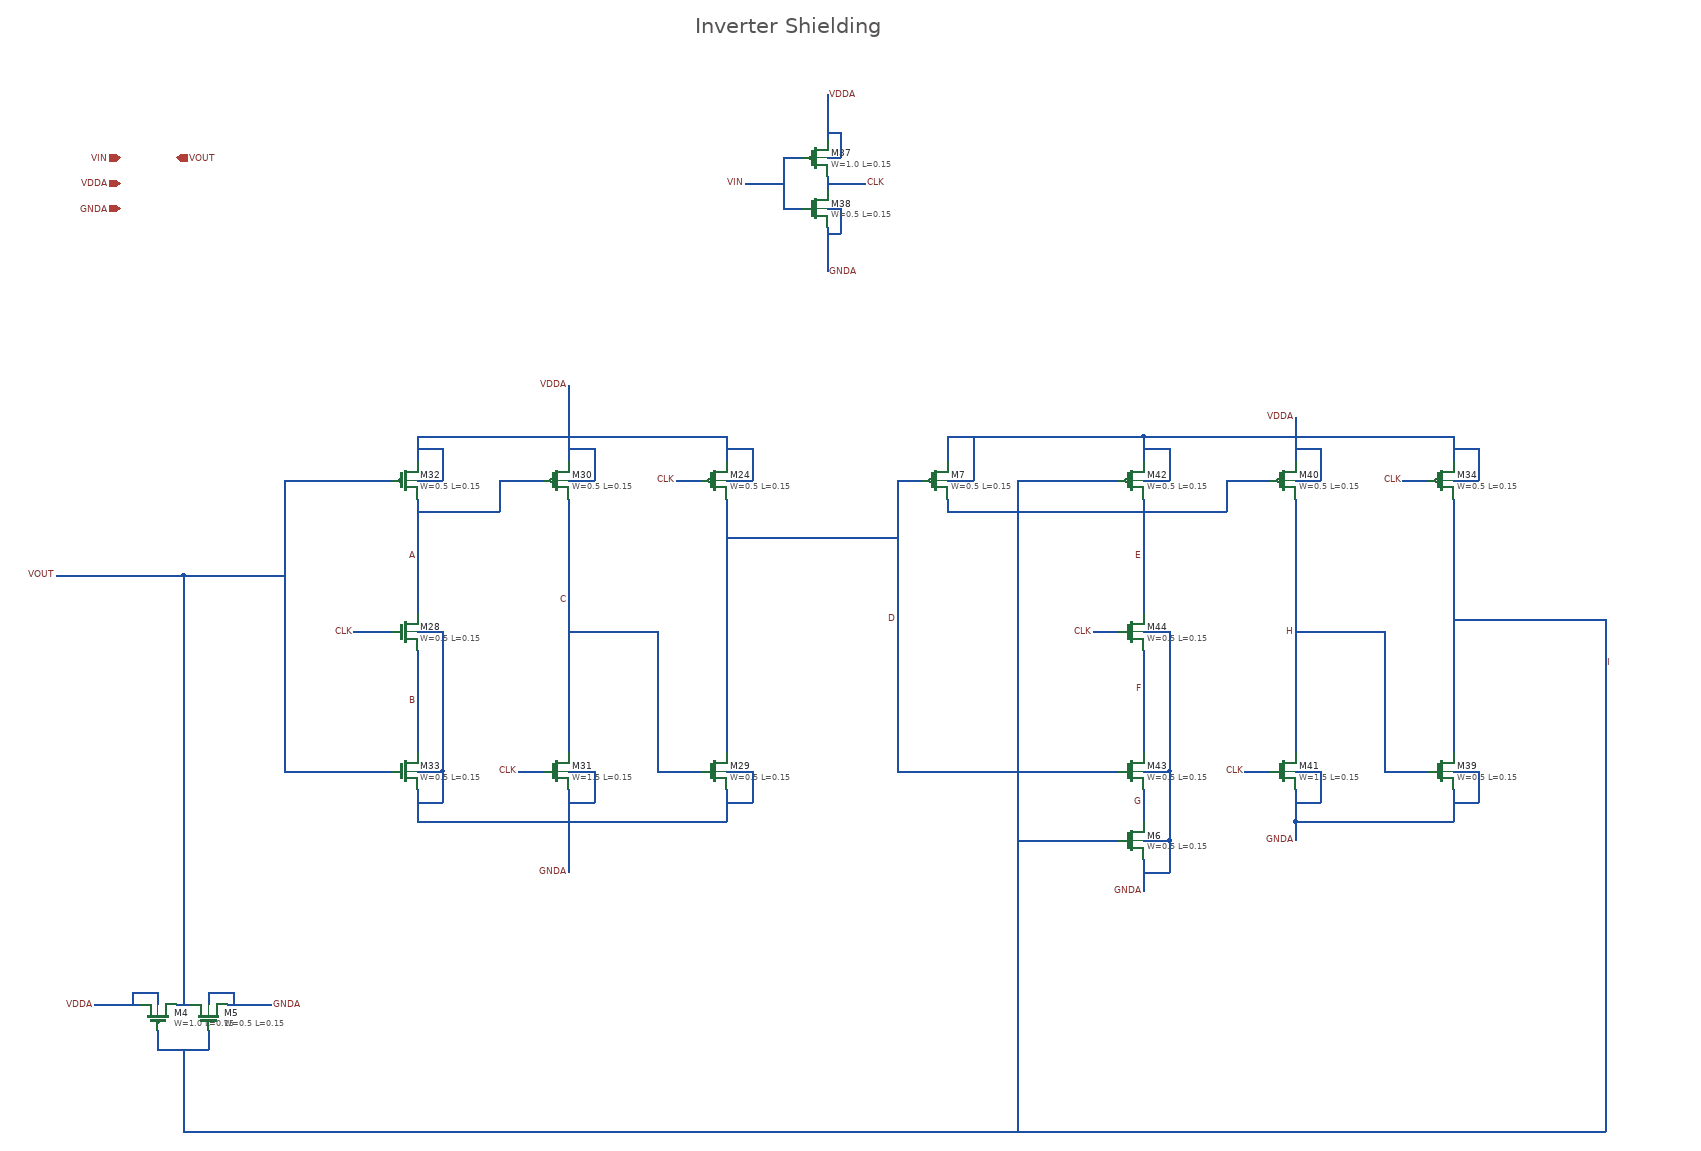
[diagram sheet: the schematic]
v {xschem version=3.4.6 file_version=1.2}
G {}
K {}
V {}
S {}
E {}
T {Inverter Shielding} 2280 -2010 0 0 1 1 {}
N 2330 -1350 2330 -1310 {
lab=VDDA}
N 2330 -1280 2370 -1280 {
lab=VDDA}
N 2370 -1330 2370 -1280 {
lab=VDDA}
N 2330 -1330 2370 -1330 {
lab=VDDA}
N 2330 -770 2370 -770 {
lab=GNDA}
N 2330 -790 2330 -740 {
lab=GNDA}
N 2330 -820 2370 -820 {
lab=GNDA}
N 2080 -1350 2080 -1310 {
lab=VDDA}
N 2080 -1280 2120 -1280 {
lab=VDDA}
N 2120 -1330 2120 -1280 {
lab=VDDA}
N 2080 -1330 2120 -1330 {
lab=VDDA}
N 2080 -770 2120 -770 {
lab=GNDA}
N 2080 -790 2080 -740 {
lab=GNDA}
N 2080 -820 2120 -820 {
lab=GNDA}
N 1840 -1350 1840 -1310 {
lab=VDDA}
N 1840 -1280 1880 -1280 {
lab=VDDA}
N 1880 -1330 1880 -1280 {
lab=VDDA}
N 1840 -1330 1880 -1330 {
lab=VDDA}
N 1840 -770 1880 -770 {
lab=GNDA}
N 1840 -790 1840 -740 {
lab=GNDA}
N 1840 -820 1880 -820 {
lab=GNDA}
N 2080 -1040 2220 -1040 {
lab=C}
N 1630 -1280 1800 -1280 {
lab=VOUT}
N 1630 -1280 1630 -910 {
lab=VOUT}
N 1740 -1040 1800 -1040 {
lab=CLK}
N 1880 -820 1880 -770 {
lab=GNDA}
N 2370 -820 2370 -770 {
lab=GNDA}
N 1840 -1350 2330 -1350 {
lab=VDDA}
N 2080 -1430 2080 -1350 {
lab=VDDA}
N 1840 -740 2330 -740 {
lab=GNDA}
N 2080 -740 2080 -660 {
lab=GNDA}
N 1630 -820 1800 -820 {
lab=VOUT}
N 1630 -910 1630 -820 {
lab=VOUT}
N 2000 -820 2040 -820 {
lab=CLK}
N 2120 -820 2120 -770 {
lab=GNDA}
N 2220 -820 2290 -820 {
lab=C}
N 1840 -1040 1880 -1040 {
lab=GNDA}
N 1880 -1040 1880 -820 {
lab=GNDA}
N 1840 -1230 1970 -1230 {
lab=A}
N 1970 -1280 1970 -1230 {
lab=A}
N 1970 -1280 2040 -1280 {
lab=A}
N 2250 -1280 2290 -1280 {
lab=CLK}
N 3480 -1350 3480 -1310 {
lab=VDDA}
N 3480 -1280 3520 -1280 {
lab=VDDA}
N 3520 -1330 3520 -1280 {
lab=VDDA}
N 3480 -1330 3520 -1330 {
lab=VDDA}
N 3480 -770 3520 -770 {
lab=GNDA}
N 3480 -790 3480 -740 {
lab=GNDA}
N 3480 -820 3520 -820 {
lab=GNDA}
N 3230 -1350 3230 -1310 {
lab=VDDA}
N 3230 -1280 3270 -1280 {
lab=VDDA}
N 3270 -1330 3270 -1280 {
lab=VDDA}
N 3230 -1330 3270 -1330 {
lab=VDDA}
N 3230 -770 3270 -770 {
lab=GNDA}
N 3230 -790 3230 -740 {
lab=GNDA}
N 3230 -820 3270 -820 {
lab=GNDA}
N 2990 -1350 2990 -1310 {
lab=VDDA}
N 2990 -1280 3030 -1280 {
lab=VDDA}
N 3030 -1330 3030 -1280 {
lab=VDDA}
N 2990 -1330 3030 -1330 {
lab=VDDA}
N 2990 -790 2990 -740 {
lab=G}
N 2990 -820 3030 -820 {
lab=GNDA}
N 3230 -1040 3370 -1040 {
lab=H}
N 2910 -1040 2950 -1040 {
lab=CLK}
N 3030 -820 3030 -770 {
lab=GNDA}
N 3520 -820 3520 -770 {
lab=GNDA}
N 2990 -1350 3480 -1350 {
lab=VDDA}
N 3230 -1380 3230 -1350 {
lab=VDDA}
N 3230 -740 3230 -710 {
lab=GNDA}
N 3150 -820 3190 -820 {
lab=CLK}
N 3270 -820 3270 -770 {
lab=GNDA}
N 3370 -820 3440 -820 {
lab=H}
N 2990 -1040 3030 -1040 {
lab=GNDA}
N 3030 -1040 3030 -820 {
lab=GNDA}
N 2990 -1230 3120 -1230 {
lab=E}
N 3120 -1280 3120 -1230 {
lab=E}
N 3120 -1280 3190 -1280 {
lab=E}
N 3400 -1280 3440 -1280 {
lab=CLK}
N 1460 -450 1480 -450 {
lab=VOUT}
N 1430 -410 1430 -380 {
lab=H}
N 1430 -380 1510 -380 {
lab=H}
N 1510 -410 1510 -380 {
lab=H}
N 1510 -470 1510 -450 {
lab=GNDA}
N 1510 -470 1550 -470 {
lab=GNDA}
N 1550 -470 1550 -450 {
lab=GNDA}
N 1330 -450 1400 -450 {
lab=VDDA}
N 1390 -470 1390 -450 {
lab=VDDA}
N 1390 -470 1430 -470 {
lab=VDDA}
N 1430 -470 1430 -450 {
lab=VDDA}
N 3480 -1060 3720 -1060 {
lab=H}
N 3720 -1060 3720 -250 {
lab=H}
N 1470 -250 3720 -250 {
lab=H}
N 3230 -740 3480 -740 {
lab=GNDA}
N 2990 -680 2990 -630 {
lab=GNDA}
N 3030 -770 3030 -710 {
lab=GNDA}
N 2990 -710 3030 -710 {
lab=GNDA}
N 3030 -710 3030 -660 {
lab=GNDA}
N 2990 -660 3030 -660 {
lab=GNDA}
N 2680 -1350 2680 -1310 {
lab=VDDA}
N 2680 -1350 2990 -1350 {
lab=VDDA}
N 2680 -1280 2720 -1280 {
lab=VDDA}
N 2720 -1350 2720 -1280 {
lab=VDDA}
N 2680 -1250 2680 -1230 {
lab=E}
N 2680 -1230 2990 -1230 {
lab=E}
N 2790 -1280 2950 -1280 {
lab=H}
N 2790 -710 2950 -710 {
lab=H}
N 2600 -1280 2600 -820 {
lab=D}
N 2600 -1280 2640 -1280 {
lab=D}
N 1470 -1130 1630 -1130 {
lab=VOUT}
N 1470 -380 1470 -250 {
lab=H}
N 1470 -1130 1470 -450 {
lab=VOUT}
N 2330 -1190 2600 -1190 {
lab=D}
N 2600 -820 2950 -820 {
lab=D}
N 2790 -1280 2790 -250 {
lab=H}
N 1840 -1250 1840 -1070 {
lab=A}
N 1840 -1010 1840 -850 {
lab=B}
N 2080 -1250 2080 -850 {
lab=C}
N 2220 -1040 2220 -820 {
lab=C}
N 2330 -1250 2330 -850 {
lab=D}
N 2990 -1010 2990 -850 {
lab=F}
N 2990 -1250 2990 -1070 {
lab=E}
N 3230 -1250 3230 -850 {
lab=H}
N 3370 -1040 3370 -820 {
lab=H}
N 3480 -1250 3480 -850 {
lab=H}
N 1540 -450 1610 -450 {
lab=GNDA}
N 1270 -1130 1470 -1130 {
lab=VOUT}
N 2490 -1760 2490 -1740 {
lab=CLK}
N 2420 -1790 2450 -1790 {
lab=VIN}
N 2420 -1790 2420 -1710 {
lab=VIN}
N 2420 -1710 2450 -1710 {
lab=VIN}
N 2490 -1710 2510 -1710 {
lab=GNDA}
N 2510 -1710 2510 -1670 {
lab=GNDA}
N 2490 -1670 2510 -1670 {
lab=GNDA}
N 2490 -1890 2490 -1820 {
lab=VDDA}
N 2490 -1830 2510 -1830 {
lab=VDDA}
N 2510 -1830 2510 -1790 {
lab=VDDA}
N 2490 -1790 2510 -1790 {
lab=VDDA}
N 2490 -1680 2490 -1610 {
lab=GNDA}
N 2360 -1750 2420 -1750 {
lab=VIN}
N 2490 -1750 2550 -1750 {
lab=CLK}
C {sky130_fd_pr/pfet_01v8.sym} 2310 -1280 0 0 {name=M24
L=0.15
W=0.5
nf=1
mult=1
ad="'int((nf+1)/2) * W/nf * 0.29'" 
pd="'2*int((nf+1)/2) * (W/nf + 0.29)'"
as="'int((nf+2)/2) * W/nf * 0.29'" 
ps="'2*int((nf+2)/2) * (W/nf + 0.29)'"
nrd="'0.29 / W'" nrs="'0.29 / W'"
sa=0 sb=0 sd=0
model=pfet_01v8
spiceprefix=X
}
C {sky130_fd_pr/nfet_01v8.sym} 2310 -820 0 0 {name=M29
L=0.15
W=0.5
nf=1 
mult=1
ad="'int((nf+1)/2) * W/nf * 0.29'" 
pd="'2*int((nf+1)/2) * (W/nf + 0.29)'"
as="'int((nf+2)/2) * W/nf * 0.29'" 
ps="'2*int((nf+2)/2) * (W/nf + 0.29)'"
nrd="'0.29 / W'" nrs="'0.29 / W'"
sa=0 sb=0 sd=0
model=nfet_01v8
spiceprefix=X
}
C {sky130_fd_pr/pfet_01v8.sym} 2060 -1280 0 0 {name=M30
L=0.15
W=0.5
nf=1
mult=1
ad="'int((nf+1)/2) * W/nf * 0.29'" 
pd="'2*int((nf+1)/2) * (W/nf + 0.29)'"
as="'int((nf+2)/2) * W/nf * 0.29'" 
ps="'2*int((nf+2)/2) * (W/nf + 0.29)'"
nrd="'0.29 / W'" nrs="'0.29 / W'"
sa=0 sb=0 sd=0
model=pfet_01v8
spiceprefix=X
}
C {sky130_fd_pr/nfet_01v8.sym} 2060 -820 0 0 {name=M31
L=0.15
W=1.5
nf=1 
mult=1
ad="'int((nf+1)/2) * W/nf * 0.29'" 
pd="'2*int((nf+1)/2) * (W/nf + 0.29)'"
as="'int((nf+2)/2) * W/nf * 0.29'" 
ps="'2*int((nf+2)/2) * (W/nf + 0.29)'"
nrd="'0.29 / W'" nrs="'0.29 / W'"
sa=0 sb=0 sd=0
model=nfet_01v8
spiceprefix=X
}
C {sky130_fd_pr/pfet_01v8.sym} 1820 -1280 0 0 {name=M32
L=0.15
W=0.5
nf=1
mult=1
ad="'int((nf+1)/2) * W/nf * 0.29'" 
pd="'2*int((nf+1)/2) * (W/nf + 0.29)'"
as="'int((nf+2)/2) * W/nf * 0.29'" 
ps="'2*int((nf+2)/2) * (W/nf + 0.29)'"
nrd="'0.29 / W'" nrs="'0.29 / W'"
sa=0 sb=0 sd=0
model=pfet_01v8
spiceprefix=X
}
C {sky130_fd_pr/nfet_01v8.sym} 1820 -820 0 0 {name=M33
L=0.15
W=0.5
nf=1 
mult=1
ad="'int((nf+1)/2) * W/nf * 0.29'" 
pd="'2*int((nf+1)/2) * (W/nf + 0.29)'"
as="'int((nf+2)/2) * W/nf * 0.29'" 
ps="'2*int((nf+2)/2) * (W/nf + 0.29)'"
nrd="'0.29 / W'" nrs="'0.29 / W'"
sa=0 sb=0 sd=0
model=nfet_01v8
spiceprefix=X
}
C {devices/lab_pin.sym} 1740 -1040 0 0 {name=p31 sig_type=std_logic lab=CLK}
C {devices/lab_pin.sym} 2000 -820 0 0 {name=p36 sig_type=std_logic lab=CLK}
C {sky130_fd_pr/nfet_01v8.sym} 1820 -1040 0 0 {name=M28
L=0.15
W=0.5
nf=1 
mult=1
ad="'int((nf+1)/2) * W/nf * 0.29'" 
pd="'2*int((nf+1)/2) * (W/nf + 0.29)'"
as="'int((nf+2)/2) * W/nf * 0.29'" 
ps="'2*int((nf+2)/2) * (W/nf + 0.29)'"
nrd="'0.29 / W'" nrs="'0.29 / W'"
sa=0 sb=0 sd=0
model=nfet_01v8
spiceprefix=X
}
C {devices/lab_pin.sym} 2250 -1280 0 0 {name=p32 sig_type=std_logic lab=CLK}
C {sky130_fd_pr/pfet_01v8.sym} 3460 -1280 0 0 {name=M34
L=0.15
W=0.5
nf=1
mult=1
ad="'int((nf+1)/2) * W/nf * 0.29'" 
pd="'2*int((nf+1)/2) * (W/nf + 0.29)'"
as="'int((nf+2)/2) * W/nf * 0.29'" 
ps="'2*int((nf+2)/2) * (W/nf + 0.29)'"
nrd="'0.29 / W'" nrs="'0.29 / W'"
sa=0 sb=0 sd=0
model=pfet_01v8
spiceprefix=X
}
C {sky130_fd_pr/nfet_01v8.sym} 3460 -820 0 0 {name=M39
L=0.15
W=0.5
nf=1 
mult=1
ad="'int((nf+1)/2) * W/nf * 0.29'" 
pd="'2*int((nf+1)/2) * (W/nf + 0.29)'"
as="'int((nf+2)/2) * W/nf * 0.29'" 
ps="'2*int((nf+2)/2) * (W/nf + 0.29)'"
nrd="'0.29 / W'" nrs="'0.29 / W'"
sa=0 sb=0 sd=0
model=nfet_01v8
spiceprefix=X
}
C {sky130_fd_pr/pfet_01v8.sym} 3210 -1280 0 0 {name=M40
L=0.15
W=0.5
nf=1
mult=1
ad="'int((nf+1)/2) * W/nf * 0.29'" 
pd="'2*int((nf+1)/2) * (W/nf + 0.29)'"
as="'int((nf+2)/2) * W/nf * 0.29'" 
ps="'2*int((nf+2)/2) * (W/nf + 0.29)'"
nrd="'0.29 / W'" nrs="'0.29 / W'"
sa=0 sb=0 sd=0
model=pfet_01v8
spiceprefix=X
}
C {sky130_fd_pr/nfet_01v8.sym} 3210 -820 0 0 {name=M41
L=0.15
W=1.5
nf=1 
mult=1
ad="'int((nf+1)/2) * W/nf * 0.29'" 
pd="'2*int((nf+1)/2) * (W/nf + 0.29)'"
as="'int((nf+2)/2) * W/nf * 0.29'" 
ps="'2*int((nf+2)/2) * (W/nf + 0.29)'"
nrd="'0.29 / W'" nrs="'0.29 / W'"
sa=0 sb=0 sd=0
model=nfet_01v8
spiceprefix=X
}
C {sky130_fd_pr/pfet_01v8.sym} 2970 -1280 0 0 {name=M42
L=0.15
W=0.5
nf=1
mult=1
ad="'int((nf+1)/2) * W/nf * 0.29'" 
pd="'2*int((nf+1)/2) * (W/nf + 0.29)'"
as="'int((nf+2)/2) * W/nf * 0.29'" 
ps="'2*int((nf+2)/2) * (W/nf + 0.29)'"
nrd="'0.29 / W'" nrs="'0.29 / W'"
sa=0 sb=0 sd=0
model=pfet_01v8
spiceprefix=X
}
C {sky130_fd_pr/nfet_01v8.sym} 2970 -820 0 0 {name=M43
L=0.15
W=0.5
nf=1 
mult=1
ad="'int((nf+1)/2) * W/nf * 0.29'" 
pd="'2*int((nf+1)/2) * (W/nf + 0.29)'"
as="'int((nf+2)/2) * W/nf * 0.29'" 
ps="'2*int((nf+2)/2) * (W/nf + 0.29)'"
nrd="'0.29 / W'" nrs="'0.29 / W'"
sa=0 sb=0 sd=0
model=nfet_01v8
spiceprefix=X
}
C {devices/lab_pin.sym} 2910 -1040 0 0 {name=p40 sig_type=std_logic lab=CLK}
C {devices/lab_pin.sym} 3150 -820 0 0 {name=p41 sig_type=std_logic lab=CLK}
C {sky130_fd_pr/nfet_01v8.sym} 2970 -1040 0 0 {name=M44
L=0.15
W=0.5
nf=1 
mult=1
ad="'int((nf+1)/2) * W/nf * 0.29'" 
pd="'2*int((nf+1)/2) * (W/nf + 0.29)'"
as="'int((nf+2)/2) * W/nf * 0.29'" 
ps="'2*int((nf+2)/2) * (W/nf + 0.29)'"
nrd="'0.29 / W'" nrs="'0.29 / W'"
sa=0 sb=0 sd=0
model=nfet_01v8
spiceprefix=X
}
C {devices/lab_pin.sym} 3400 -1280 0 0 {name=p44 sig_type=std_logic lab=CLK}
C {sky130_fd_pr/pfet_01v8.sym} 1430 -430 3 0 {name=M4
L=0.15
W=1.0
nf=2
mult=1
ad="'int((nf+1)/2) * W/nf * 0.29'" 
pd="'2*int((nf+1)/2) * (W/nf + 0.29)'"
as="'int((nf+2)/2) * W/nf * 0.29'" 
ps="'2*int((nf+2)/2) * (W/nf + 0.29)'"
nrd="'0.29 / W'" nrs="'0.29 / W'"
sa=0 sb=0 sd=0
model=pfet_01v8
spiceprefix=X
}
C {sky130_fd_pr/nfet_01v8.sym} 1510 -430 3 0 {name=M5
L=0.15
W=0.5
nf=1 
mult=1
ad="'int((nf+1)/2) * W/nf * 0.29'" 
pd="'2*int((nf+1)/2) * (W/nf + 0.29)'"
as="'int((nf+2)/2) * W/nf * 0.29'" 
ps="'2*int((nf+2)/2) * (W/nf + 0.29)'"
nrd="'0.29 / W'" nrs="'0.29 / W'"
sa=0 sb=0 sd=0
model=nfet_01v8
spiceprefix=X
}
C {sky130_fd_pr/nfet_01v8.sym} 2970 -710 0 0 {name=M6
L=0.15
W=0.5
nf=1 
mult=1
ad="'int((nf+1)/2) * W/nf * 0.29'" 
pd="'2*int((nf+1)/2) * (W/nf + 0.29)'"
as="'int((nf+2)/2) * W/nf * 0.29'" 
ps="'2*int((nf+2)/2) * (W/nf + 0.29)'"
nrd="'0.29 / W'" nrs="'0.29 / W'"
sa=0 sb=0 sd=0
model=nfet_01v8
spiceprefix=X
}
C {sky130_fd_pr/pfet_01v8.sym} 2660 -1280 0 0 {name=M7
L=0.15
W=0.5
nf=1
mult=1
ad="'int((nf+1)/2) * W/nf * 0.29'" 
pd="'2*int((nf+1)/2) * (W/nf + 0.29)'"
as="'int((nf+2)/2) * W/nf * 0.29'" 
ps="'2*int((nf+2)/2) * (W/nf + 0.29)'"
nrd="'0.29 / W'" nrs="'0.29 / W'"
sa=0 sb=0 sd=0
model=pfet_01v8
spiceprefix=X
}
C {devices/lab_pin.sym} 1610 -450 0 1 {name=p2 sig_type=std_logic lab=GNDA}
C {devices/lab_pin.sym} 1330 -450 0 0 {name=p1 sig_type=std_logic lab=VDDA}
C {devices/lab_pin.sym} 2080 -660 0 0 {name=p3 sig_type=std_logic lab=GNDA}
C {devices/lab_pin.sym} 2080 -1430 0 0 {name=p4 sig_type=std_logic lab=VDDA}
C {devices/lab_pin.sym} 3230 -1380 0 0 {name=p5 sig_type=std_logic lab=VDDA}
C {devices/lab_pin.sym} 3230 -710 0 0 {name=p6 sig_type=std_logic lab=GNDA}
C {devices/lab_pin.sym} 2990 -630 0 0 {name=p7 sig_type=std_logic lab=GNDA}
C {devices/lab_pin.sym} 1270 -1130 0 0 {name=p8 sig_type=std_logic lab=VOUT}
C {devices/ipin.sym} 1370 -1790 0 0 {name=p9 lab=VIN}
C {devices/opin.sym} 1460 -1790 0 0 {name=p10 lab=VOUT}
C {devices/ipin.sym} 1370 -1750 0 0 {name=p11 lab=VDDA}
C {devices/ipin.sym} 1370 -1710 0 0 {name=p12 lab=GNDA}
C {sky130_fd_pr/pfet_01v8.sym} 2470 -1790 0 0 {name=M37
L=0.15
W=1.0
nf=2
mult=1
ad="'int((nf+1)/2) * W/nf * 0.29'" 
pd="'2*int((nf+1)/2) * (W/nf + 0.29)'"
as="'int((nf+2)/2) * W/nf * 0.29'" 
ps="'2*int((nf+2)/2) * (W/nf + 0.29)'"
nrd="'0.29 / W'" nrs="'0.29 / W'"
sa=0 sb=0 sd=0
model=pfet_01v8
spiceprefix=X
}
C {sky130_fd_pr/nfet_01v8.sym} 2470 -1710 0 0 {name=M38
L=0.15
W=0.5
nf=1 
mult=1
ad="'int((nf+1)/2) * W/nf * 0.29'" 
pd="'2*int((nf+1)/2) * (W/nf + 0.29)'"
as="'int((nf+2)/2) * W/nf * 0.29'" 
ps="'2*int((nf+2)/2) * (W/nf + 0.29)'"
nrd="'0.29 / W'" nrs="'0.29 / W'"
sa=0 sb=0 sd=0
model=nfet_01v8
spiceprefix=X
}
C {devices/lab_pin.sym} 2490 -1610 0 1 {name=p29 sig_type=std_logic lab=GNDA}
C {devices/lab_pin.sym} 2490 -1890 2 0 {name=p37 sig_type=std_logic lab=VDDA}
C {devices/lab_pin.sym} 2360 -1750 0 0 {name=p13 sig_type=std_logic lab=VIN}
C {devices/lab_pin.sym} 2550 -1750 0 1 {name=p14 sig_type=std_logic lab=CLK}
C {devices/lab_pin.sym} 1840 -1160 0 0 {name=p15 sig_type=std_logic lab=A}
C {devices/lab_pin.sym} 1840 -930 0 0 {name=p16 sig_type=std_logic lab=B}
C {devices/lab_pin.sym} 2080 -1090 0 0 {name=p17 sig_type=std_logic lab=C}
C {devices/lab_pin.sym} 2600 -1060 0 0 {name=p18 sig_type=std_logic lab=D}
C {devices/lab_pin.sym} 2990 -1160 0 0 {name=p19 sig_type=std_logic lab=E}
C {devices/lab_pin.sym} 2990 -950 0 0 {name=p20 sig_type=std_logic lab=F}
C {devices/lab_pin.sym} 2990 -770 0 0 {name=p21 sig_type=std_logic lab=G}
C {devices/lab_pin.sym} 3230 -1040 0 0 {name=p22 sig_type=std_logic lab=H}
C {devices/lab_pin.sym} 3720 -990 0 1 {name=p23 sig_type=std_logic lab=I}
